VERSION 5.7 ;
  NOWIREEXTENSIONATPIN ON ;
  DIVIDERCHAR "/" ;
  BUSBITCHARS "[]" ;
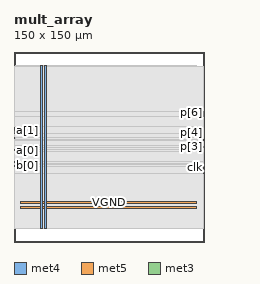
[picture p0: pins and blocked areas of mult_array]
MACRO mult_array
  CLASS BLOCK ;
  FOREIGN mult_array ;
  ORIGIN 0.000 0.000 ;
  SIZE 150.000 BY 150.000 ;
  PIN VGND
    DIRECTION INOUT ;
    USE GROUND ;
    PORT
      LAYER met4 ;
        RECT 24.340 10.640 25.940 138.960 ;
    END
    PORT
      LAYER met5 ;
        RECT 5.520 30.030 144.440 31.630 ;
    END
  END VGND
  PIN VPWR
    DIRECTION INOUT ;
    USE POWER ;
    PORT
      LAYER met4 ;
        RECT 21.040 10.640 22.640 138.960 ;
    END
    PORT
      LAYER met5 ;
        RECT 5.520 26.730 144.440 28.330 ;
    END
  END VPWR
  PIN a[0]
    DIRECTION INPUT ;
    USE SIGNAL ;
    ANTENNAGATEAREA 0.159000 ;
    PORT
      LAYER met3 ;
        RECT 0.000 72.120 0.600 72.720 ;
    END
  END a[0]
  PIN a[1]
    DIRECTION INPUT ;
    USE SIGNAL ;
    ANTENNAGATEAREA 0.159000 ;
    PORT
      LAYER met3 ;
        RECT 0.000 81.640 0.600 82.240 ;
    END
  END a[1]
  PIN a[2]
    DIRECTION INPUT ;
    USE SIGNAL ;
    ANTENNAGATEAREA 0.159000 ;
    PORT
      LAYER met3 ;
        RECT 0.000 87.080 0.600 87.680 ;
    END
  END a[2]
  PIN a[3]
    DIRECTION INPUT ;
    USE SIGNAL ;
    ANTENNAGATEAREA 0.159000 ;
    PORT
      LAYER met3 ;
        RECT 0.000 89.800 0.600 90.400 ;
    END
  END a[3]
  PIN b[0]
    DIRECTION INPUT ;
    USE SIGNAL ;
    ANTENNAGATEAREA 0.159000 ;
    PORT
      LAYER met3 ;
        RECT 0.000 59.880 0.600 60.480 ;
    END
  END b[0]
  PIN b[1]
    DIRECTION INPUT ;
    USE SIGNAL ;
    ANTENNAGATEAREA 0.159000 ;
    PORT
      LAYER met3 ;
        RECT 0.000 62.600 0.600 63.200 ;
    END
  END b[1]
  PIN b[2]
    DIRECTION INPUT ;
    USE SIGNAL ;
    ANTENNAGATEAREA 0.159000 ;
    PORT
      LAYER met3 ;
        RECT 0.000 85.720 0.600 86.320 ;
    END
  END b[2]
  PIN b[3]
    DIRECTION INPUT ;
    USE SIGNAL ;
    ANTENNAGATEAREA 0.159000 ;
    PORT
      LAYER met3 ;
        RECT 0.000 88.440 0.600 89.040 ;
    END
  END b[3]
  PIN clk
    DIRECTION INPUT ;
    USE SIGNAL ;
    ANTENNAGATEAREA 0.852000 ;
    PORT
      LAYER met3 ;
        RECT 149.400 58.520 150.000 59.120 ;
    END
  END clk
  PIN p[0]
    DIRECTION OUTPUT ;
    USE SIGNAL ;
    ANTENNADIFFAREA 0.445500 ;
    PORT
      LAYER met3 ;
        RECT 149.400 55.800 150.000 56.400 ;
    END
  END p[0]
  PIN p[1]
    DIRECTION OUTPUT ;
    USE SIGNAL ;
    ANTENNADIFFAREA 0.445500 ;
    PORT
      LAYER met3 ;
        RECT 149.400 57.160 150.000 57.760 ;
    END
  END p[1]
  PIN p[2]
    DIRECTION OUTPUT ;
    USE SIGNAL ;
    ANTENNADIFFAREA 0.445500 ;
    PORT
      LAYER met3 ;
        RECT 149.400 54.440 150.000 55.040 ;
    END
  END p[2]
  PIN p[3]
    DIRECTION OUTPUT ;
    USE SIGNAL ;
    ANTENNADIFFAREA 0.445500 ;
    PORT
      LAYER met3 ;
        RECT 149.400 74.840 150.000 75.440 ;
    END
  END p[3]
  PIN p[4]
    DIRECTION OUTPUT ;
    USE SIGNAL ;
    ANTENNADIFFAREA 0.445500 ;
    PORT
      LAYER met3 ;
        RECT 149.400 80.280 150.000 80.880 ;
    END
  END p[4]
  PIN p[5]
    DIRECTION OUTPUT ;
    USE SIGNAL ;
    ANTENNADIFFAREA 0.445500 ;
    PORT
      LAYER met3 ;
        RECT 149.400 99.320 150.000 99.920 ;
    END
  END p[5]
  PIN p[6]
    DIRECTION OUTPUT ;
    USE SIGNAL ;
    ANTENNADIFFAREA 0.445500 ;
    PORT
      LAYER met3 ;
        RECT 149.400 102.040 150.000 102.640 ;
    END
  END p[6]
  PIN p[7]
    DIRECTION OUTPUT ;
    USE SIGNAL ;
    ANTENNADIFFAREA 0.445500 ;
    PORT
      LAYER met3 ;
        RECT 149.400 100.680 150.000 101.280 ;
    END
  END p[7]
  PIN rst_n
    DIRECTION INPUT ;
    USE SIGNAL ;
    ANTENNAGATEAREA 0.159000 ;
    PORT
      LAYER met3 ;
        RECT 149.400 59.880 150.000 60.480 ;
    END
  END rst_n
  OBS
      LAYER nwell ;
        RECT 5.330 10.795 144.630 138.910 ;
      LAYER li1 ;
        RECT 5.520 10.795 144.440 138.805 ;
      LAYER met1 ;
        RECT 0.990 10.640 144.440 138.960 ;
      LAYER met2 ;
        RECT 1.010 10.695 142.970 138.905 ;
      LAYER met3 ;
        RECT 0.600 103.040 149.400 138.885 ;
        RECT 0.600 98.920 149.000 103.040 ;
        RECT 0.600 90.800 149.400 98.920 ;
        RECT 1.000 85.320 149.400 90.800 ;
        RECT 0.600 82.640 149.400 85.320 ;
        RECT 1.000 81.280 149.400 82.640 ;
        RECT 1.000 81.240 149.000 81.280 ;
        RECT 0.600 79.880 149.000 81.240 ;
        RECT 0.600 75.840 149.400 79.880 ;
        RECT 0.600 74.440 149.000 75.840 ;
        RECT 0.600 73.120 149.400 74.440 ;
        RECT 1.000 71.720 149.400 73.120 ;
        RECT 0.600 63.600 149.400 71.720 ;
        RECT 1.000 62.200 149.400 63.600 ;
        RECT 0.600 60.880 149.400 62.200 ;
        RECT 1.000 59.480 149.000 60.880 ;
        RECT 0.600 54.040 149.000 59.480 ;
        RECT 0.600 10.715 149.400 54.040 ;
  END
END mult_array
END LIBRARY

